VERSION 5.8 ;
BUSBITCHARS "[]" ;
DIVIDERCHAR "/" ;
UNITS
    DATABASE MICRONS 1000 ;
END UNITS

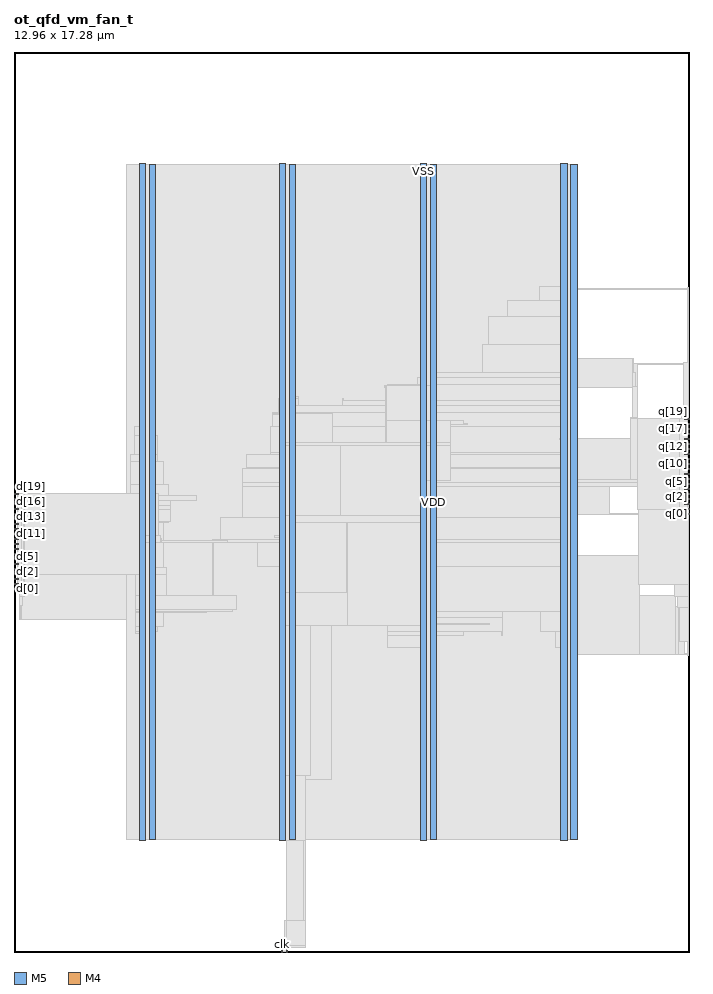
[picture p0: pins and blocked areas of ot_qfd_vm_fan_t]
MACRO ot_qfd_vm_fan_t
  FOREIGN ot_qfd_vm_fan_t 0 0 ;
  CLASS BLOCK ;
  SIZE 12.96 BY 17.28 ;
  PIN clk
    DIRECTION INPUT ;
    USE SIGNAL ;
    PORT
      LAYER M5 ;
        RECT  5.136 0 5.16 0.084 ;
    END
  END clk
  PIN d[0]
    DIRECTION INPUT ;
    USE SIGNAL ;
    PORT
      LAYER M4 ;
        RECT  0 6.96 0.084 6.984 ;
    END
  END d[0]
  PIN d[10]
    DIRECTION INPUT ;
    USE SIGNAL ;
    PORT
      LAYER M4 ;
        RECT  0 7.92 0.084 7.944 ;
    END
  END d[10]
  PIN d[11]
    DIRECTION INPUT ;
    USE SIGNAL ;
    PORT
      LAYER M4 ;
        RECT  0 8.016 0.084 8.04 ;
    END
  END d[11]
  PIN d[12]
    DIRECTION INPUT ;
    USE SIGNAL ;
    PORT
      LAYER M4 ;
        RECT  0 8.112 0.084 8.136 ;
    END
  END d[12]
  PIN d[13]
    DIRECTION INPUT ;
    USE SIGNAL ;
    PORT
      LAYER M4 ;
        RECT  0 8.208 0.084 8.232 ;
    END
  END d[13]
  PIN d[14]
    DIRECTION INPUT ;
    USE SIGNAL ;
    PORT
      LAYER M4 ;
        RECT  0 8.304 0.084 8.328 ;
    END
  END d[14]
  PIN d[15]
    DIRECTION INPUT ;
    USE SIGNAL ;
    PORT
      LAYER M4 ;
        RECT  0 8.4 0.084 8.424 ;
    END
  END d[15]
  PIN d[16]
    DIRECTION INPUT ;
    USE SIGNAL ;
    PORT
      LAYER M4 ;
        RECT  0 8.496 0.084 8.52 ;
    END
  END d[16]
  PIN d[17]
    DIRECTION INPUT ;
    USE SIGNAL ;
    PORT
      LAYER M4 ;
        RECT  0 8.592 0.084 8.616 ;
    END
  END d[17]
  PIN d[18]
    DIRECTION INPUT ;
    USE SIGNAL ;
    PORT
      LAYER M4 ;
        RECT  0 8.688 0.084 8.712 ;
    END
  END d[18]
  PIN d[19]
    DIRECTION INPUT ;
    USE SIGNAL ;
    PORT
      LAYER M4 ;
        RECT  0 8.784 0.084 8.808 ;
    END
  END d[19]
  PIN d[1]
    DIRECTION INPUT ;
    USE SIGNAL ;
    PORT
      LAYER M4 ;
        RECT  0 7.056 0.084 7.08 ;
    END
  END d[1]
  PIN d[2]
    DIRECTION INPUT ;
    USE SIGNAL ;
    PORT
      LAYER M4 ;
        RECT  0 7.152 0.084 7.176 ;
    END
  END d[2]
  PIN d[3]
    DIRECTION INPUT ;
    USE SIGNAL ;
    PORT
      LAYER M4 ;
        RECT  0 7.248 0.084 7.272 ;
    END
  END d[3]
  PIN d[4]
    DIRECTION INPUT ;
    USE SIGNAL ;
    PORT
      LAYER M4 ;
        RECT  0 7.344 0.084 7.368 ;
    END
  END d[4]
  PIN d[5]
    DIRECTION INPUT ;
    USE SIGNAL ;
    PORT
      LAYER M4 ;
        RECT  0 7.44 0.084 7.464 ;
    END
  END d[5]
  PIN d[6]
    DIRECTION INPUT ;
    USE SIGNAL ;
    PORT
      LAYER M4 ;
        RECT  0 7.536 0.084 7.56 ;
    END
  END d[6]
  PIN d[7]
    DIRECTION INPUT ;
    USE SIGNAL ;
    PORT
      LAYER M4 ;
        RECT  0 7.632 0.084 7.656 ;
    END
  END d[7]
  PIN d[8]
    DIRECTION INPUT ;
    USE SIGNAL ;
    PORT
      LAYER M4 ;
        RECT  0 7.728 0.084 7.752 ;
    END
  END d[8]
  PIN d[9]
    DIRECTION INPUT ;
    USE SIGNAL ;
    PORT
      LAYER M4 ;
        RECT  0 7.824 0.084 7.848 ;
    END
  END d[9]
  PIN me_e
    DIRECTION INPUT ;
    USE SIGNAL ;
    PORT
      LAYER M5 ;
        RECT  5.232 0 5.256 0.084 ;
    END
  END me_e
  PIN q[0]
    DIRECTION OUTPUT ;
    USE SIGNAL ;
    PORT
      LAYER M4 ;
        RECT  12.876 8.4 12.96 8.424 ;
    END
  END q[0]
  PIN q[10]
    DIRECTION OUTPUT ;
    USE SIGNAL ;
    PORT
      LAYER M4 ;
        RECT  12.876 9.36 12.96 9.384 ;
    END
  END q[10]
  PIN q[11]
    DIRECTION OUTPUT ;
    USE SIGNAL ;
    PORT
      LAYER M4 ;
        RECT  12.876 9.456 12.96 9.48 ;
    END
  END q[11]
  PIN q[12]
    DIRECTION OUTPUT ;
    USE SIGNAL ;
    PORT
      LAYER M4 ;
        RECT  12.876 9.552 12.96 9.576 ;
    END
  END q[12]
  PIN q[13]
    DIRECTION OUTPUT ;
    USE SIGNAL ;
    PORT
      LAYER M4 ;
        RECT  12.876 9.648 12.96 9.672 ;
    END
  END q[13]
  PIN q[14]
    DIRECTION OUTPUT ;
    USE SIGNAL ;
    PORT
      LAYER M4 ;
        RECT  12.876 9.744 12.96 9.768 ;
    END
  END q[14]
  PIN q[15]
    DIRECTION OUTPUT ;
    USE SIGNAL ;
    PORT
      LAYER M4 ;
        RECT  12.876 9.84 12.96 9.864 ;
    END
  END q[15]
  PIN q[16]
    DIRECTION OUTPUT ;
    USE SIGNAL ;
    PORT
      LAYER M4 ;
        RECT  12.876 9.936 12.96 9.96 ;
    END
  END q[16]
  PIN q[17]
    DIRECTION OUTPUT ;
    USE SIGNAL ;
    PORT
      LAYER M4 ;
        RECT  12.876 10.032 12.96 10.056 ;
    END
  END q[17]
  PIN q[18]
    DIRECTION OUTPUT ;
    USE SIGNAL ;
    PORT
      LAYER M4 ;
        RECT  12.876 10.128 12.96 10.152 ;
    END
  END q[18]
  PIN q[19]
    DIRECTION OUTPUT ;
    USE SIGNAL ;
    PORT
      LAYER M4 ;
        RECT  12.876 10.224 12.96 10.248 ;
    END
  END q[19]
  PIN q[1]
    DIRECTION OUTPUT ;
    USE SIGNAL ;
    PORT
      LAYER M4 ;
        RECT  12.876 8.496 12.96 8.52 ;
    END
  END q[1]
  PIN q[2]
    DIRECTION OUTPUT ;
    USE SIGNAL ;
    PORT
      LAYER M4 ;
        RECT  12.876 8.592 12.96 8.616 ;
    END
  END q[2]
  PIN q[3]
    DIRECTION OUTPUT ;
    USE SIGNAL ;
    PORT
      LAYER M4 ;
        RECT  12.876 8.688 12.96 8.712 ;
    END
  END q[3]
  PIN q[4]
    DIRECTION OUTPUT ;
    USE SIGNAL ;
    PORT
      LAYER M4 ;
        RECT  12.876 8.784 12.96 8.808 ;
    END
  END q[4]
  PIN q[5]
    DIRECTION OUTPUT ;
    USE SIGNAL ;
    PORT
      LAYER M4 ;
        RECT  12.876 8.88 12.96 8.904 ;
    END
  END q[5]
  PIN q[6]
    DIRECTION OUTPUT ;
    USE SIGNAL ;
    PORT
      LAYER M4 ;
        RECT  12.876 8.976 12.96 9 ;
    END
  END q[6]
  PIN q[7]
    DIRECTION OUTPUT ;
    USE SIGNAL ;
    PORT
      LAYER M4 ;
        RECT  12.876 9.072 12.96 9.096 ;
    END
  END q[7]
  PIN q[8]
    DIRECTION OUTPUT ;
    USE SIGNAL ;
    PORT
      LAYER M4 ;
        RECT  12.876 9.168 12.96 9.192 ;
    END
  END q[8]
  PIN q[9]
    DIRECTION OUTPUT ;
    USE SIGNAL ;
    PORT
      LAYER M4 ;
        RECT  12.876 9.264 12.96 9.288 ;
    END
  END q[9]
  PIN VDD
    DIRECTION INOUT ;
    USE POWER ;
    PORT
      LAYER M5 ;
        RECT  10.692 2.151 10.812 15.129 ;
        RECT  7.992 2.151 8.112 15.129 ;
        RECT  5.292 2.151 5.412 15.129 ;
        RECT  2.592 2.151 2.712 15.129 ;
    END
  END VDD
  PIN VSS
    DIRECTION INOUT ;
    USE GROUND ;
    PORT
      LAYER M5 ;
        RECT  10.5 2.137 10.62 15.143 ;
        RECT  7.8 2.137 7.92 15.143 ;
        RECT  5.1 2.137 5.22 15.143 ;
        RECT  2.4 2.137 2.52 15.143 ;
    END
  END VSS
  # OT_OBS_CLOSED layer=M5 d_um=1.536 added=5
  OBS
    LAYER RVTN ;
     RECT  2.16 2.16 10.8 2.295 ;
     RECT  2.16 2.565 10.8 2.835 ;
     RECT  2.16 3.105 10.8 3.375 ;
     RECT  2.16 3.645 10.8 3.915 ;
     RECT  2.16 4.185 10.8 4.455 ;
     RECT  2.16 4.725 10.8 4.995 ;
     RECT  2.16 5.265 10.8 5.535 ;
     RECT  2.16 5.805 10.8 6.075 ;
     RECT  2.16 6.345 10.8 6.615 ;
     RECT  2.16 6.885 10.8 7.155 ;
     RECT  2.16 7.425 10.8 7.695 ;
     RECT  2.16 7.965 10.8 8.235 ;
     RECT  2.16 8.505 10.8 8.775 ;
     RECT  2.16 9.045 10.8 9.315 ;
     RECT  2.16 9.585 10.8 9.855 ;
     RECT  2.16 10.125 10.8 10.395 ;
     RECT  2.16 10.665 10.8 10.935 ;
     RECT  2.16 11.205 10.8 11.475 ;
     RECT  2.16 11.745 10.8 12.015 ;
     RECT  2.16 12.285 10.8 12.555 ;
     RECT  2.16 12.825 10.8 13.095 ;
     RECT  2.16 13.365 10.8 13.635 ;
     RECT  2.16 13.905 10.8 14.175 ;
     RECT  2.16 14.445 10.8 14.715 ;
     RECT  2.16 14.985 10.8 15.12 ;
    LAYER RVTP ;
     RECT  2.16 2.295 10.8 2.565 ;
     RECT  2.16 2.835 10.8 3.105 ;
     RECT  2.16 3.375 10.8 3.645 ;
     RECT  2.16 3.915 10.8 4.185 ;
     RECT  2.16 4.455 10.8 4.725 ;
     RECT  2.16 4.995 10.8 5.265 ;
     RECT  2.16 5.535 10.8 5.805 ;
     RECT  2.16 6.075 10.8 6.345 ;
     RECT  2.16 6.615 10.8 6.885 ;
     RECT  2.16 7.155 10.8 7.425 ;
     RECT  2.16 7.695 10.8 7.965 ;
     RECT  2.16 8.235 10.8 8.505 ;
     RECT  2.16 8.775 10.8 9.045 ;
     RECT  2.16 9.315 10.8 9.585 ;
     RECT  2.16 9.855 10.8 10.125 ;
     RECT  2.16 10.395 10.8 10.665 ;
     RECT  2.16 10.935 10.8 11.205 ;
     RECT  2.16 11.475 10.8 11.745 ;
     RECT  2.16 12.015 10.8 12.285 ;
     RECT  2.16 12.555 10.8 12.825 ;
     RECT  2.16 13.095 10.8 13.365 ;
     RECT  2.16 13.635 10.8 13.905 ;
     RECT  2.16 14.175 10.8 14.445 ;
     RECT  2.16 14.715 10.8 14.985 ;
    LAYER M1 ;
     RECT  2.16 2.151 10.8 15.129 ;
    LAYER M2 ;
     RECT  0.103 6.39 0.139 6.408 ;
     RECT  0.103 7.398 0.139 7.416 ;
     RECT  0.139 6.39 2.16 7.416 ;
     RECT  2.16 2.151 10.8 15.129 ;
     RECT  10.8 2.421 10.812 14.859 ;
     RECT  10.812 8.406 11.435 9.846 ;
     RECT  10.812 10.836 11.903 11.394 ;
     RECT  11.435 9.216 11.939 9.846 ;
     RECT  11.939 9.216 11.975 9.774 ;
     RECT  11.903 10.836 11.975 11.304 ;
     RECT  10.812 5.706 12.011 7.614 ;
     RECT  12.011 7.596 12.047 7.614 ;
     RECT  11.435 8.406 12.083 8.424 ;
     RECT  12.011 5.706 12.695 6.84 ;
     RECT  12.695 5.706 12.767 6.642 ;
     RECT  12.775 8.478 12.847 8.496 ;
     RECT  12.767 5.706 12.875 6.264 ;
     RECT  12.847 8.478 12.875 8.604 ;
     RECT  11.975 11.286 12.875 11.304 ;
     RECT  12.875 5.706 12.947 5.724 ;
     RECT  12.875 8.586 12.947 8.604 ;
     RECT  12.811 10.251 12.947 10.269 ;
     RECT  10.812 12.726 12.947 12.744 ;
    LAYER M3 ;
     RECT  5.256 0.571 5.274 2.143 ;
     RECT  2.415 2.143 2.505 2.413 ;
     RECT  5.115 2.143 5.274 2.413 ;
     RECT  7.815 2.143 7.905 2.413 ;
     RECT  10.515 2.143 10.605 2.413 ;
     RECT  5.115 2.413 5.397 2.641 ;
     RECT  5.115 2.641 5.454 3.307 ;
     RECT  7.815 2.413 8.097 5.845 ;
     RECT  10.515 2.413 10.797 5.845 ;
     RECT  12.924 5.701 12.942 5.971 ;
     RECT  7.164 5.845 8.097 6.079 ;
     RECT  2.415 2.413 2.697 6.115 ;
     RECT  2.34 6.115 2.697 6.151 ;
     RECT  7.164 6.079 8.622 6.151 ;
     RECT  9.36 6.079 9.378 6.151 ;
     RECT  10.404 5.845 10.797 6.151 ;
     RECT  2.34 6.151 2.754 6.241 ;
     RECT  5.115 3.307 6.102 6.421 ;
     RECT  7.164 6.151 9.378 6.421 ;
     RECT  2.34 6.241 2.862 6.511 ;
     RECT  2.34 6.511 3.69 6.547 ;
     RECT  5.115 6.421 9.378 6.547 ;
     RECT  10.116 6.151 10.797 6.547 ;
     RECT  2.34 6.547 4.194 6.583 ;
     RECT  12.78 5.971 12.942 6.619 ;
     RECT  0.108 6.385 0.126 6.655 ;
     RECT  0.108 6.655 0.162 6.817 ;
     RECT  12.744 6.619 12.942 6.817 ;
     RECT  2.34 6.583 4.266 6.845 ;
     RECT  12.672 6.817 12.942 7.051 ;
     RECT  0.108 6.817 0.198 7.181 ;
     RECT  2.34 6.845 2.934 7.243 ;
     RECT  2.304 7.243 2.934 7.385 ;
     RECT  5.115 6.547 10.797 7.393 ;
     RECT  0.108 7.181 0.162 7.565 ;
     RECT  3.816 6.845 3.834 7.867 ;
     RECT  4.68 7.393 10.797 7.867 ;
     RECT  3.816 7.867 10.797 7.925 ;
     RECT  0.144 7.565 0.162 7.997 ;
     RECT  2.304 7.385 2.862 8.239 ;
     RECT  2.304 8.239 2.97 8.275 ;
     RECT  3.96 7.925 10.797 8.339 ;
     RECT  2.304 8.275 3.006 8.491 ;
     RECT  2.268 8.491 3.006 8.581 ;
     RECT  11.988 7.051 12.942 8.609 ;
     RECT  11.988 8.609 12.87 8.621 ;
     RECT  2.232 8.581 3.006 8.671 ;
     RECT  2.232 8.671 3.51 8.771 ;
     RECT  11.988 8.621 12.798 8.813 ;
     RECT  4.392 8.339 10.797 8.941 ;
     RECT  11.988 8.813 12.762 8.941 ;
     RECT  2.232 8.771 2.97 8.969 ;
     RECT  4.392 8.941 12.762 9.005 ;
     RECT  4.392 9.005 12.078 9.275 ;
     RECT  4.464 9.275 12.078 9.293 ;
     RECT  2.232 8.969 2.862 9.419 ;
     RECT  2.232 9.419 2.754 9.545 ;
     RECT  4.464 9.293 11.97 9.545 ;
     RECT  4.932 9.545 11.97 9.581 ;
     RECT  2.304 9.545 2.754 9.923 ;
     RECT  2.304 9.923 2.697 10.085 ;
     RECT  4.932 9.581 10.797 10.085 ;
     RECT  12.852 10.027 12.87 10.219 ;
     RECT  12.816 10.219 12.87 10.246 ;
     RECT  11.844 9.581 11.97 10.253 ;
     RECT  12.816 10.246 12.942 10.274 ;
     RECT  4.968 10.085 10.797 10.349 ;
     RECT  5.076 10.349 10.797 10.499 ;
     RECT  6.3 10.499 10.797 10.589 ;
     RECT  5.076 10.499 5.454 10.625 ;
     RECT  6.3 10.589 6.318 10.625 ;
     RECT  5.115 10.625 5.454 10.661 ;
     RECT  11.88 10.253 11.97 10.859 ;
     RECT  7.164 10.589 10.797 10.895 ;
     RECT  7.74 10.895 10.797 11.039 ;
     RECT  7.815 11.039 10.797 11.129 ;
     RECT  11.88 10.859 11.934 11.129 ;
     RECT  12.852 10.274 12.942 11.309 ;
     RECT  11.88 11.129 11.898 11.399 ;
     RECT  9 11.129 10.797 11.669 ;
     RECT  9.108 11.669 10.797 12.209 ;
     RECT  9.468 12.209 10.797 12.515 ;
     RECT  12.924 11.309 12.942 12.749 ;
     RECT  10.08 12.515 10.797 12.785 ;
     RECT  2.415 10.085 2.697 14.867 ;
     RECT  5.115 10.661 5.397 14.867 ;
     RECT  7.815 11.129 8.097 14.867 ;
     RECT  10.515 12.785 10.797 14.867 ;
     RECT  2.415 14.867 2.505 15.137 ;
     RECT  5.115 14.867 5.205 15.137 ;
     RECT  7.815 14.867 7.905 15.137 ;
     RECT  10.515 14.867 10.605 15.137 ;
    LAYER M4 ;
     RECT  0.06 6.96 0.137 8.808 ;
     RECT  0.137 7.056 0.173 8.808 ;
     RECT  0.173 7.152 0.209 8.808 ;
     RECT  0.209 7.248 2.408 8.808 ;
     RECT  2.408 2.148 2.512 15.132 ;
     RECT  2.512 2.418 2.704 14.862 ;
     RECT  2.704 7.872 2.765 8.808 ;
     RECT  2.765 7.872 2.819 7.992 ;
     RECT  2.819 7.872 2.839 7.944 ;
     RECT  2.839 7.872 4.097 7.896 ;
     RECT  4.993 7.968 5.108 7.992 ;
     RECT  4.957 10.32 5.108 10.344 ;
     RECT  5.125 0.096 5.201 0.12 ;
     RECT  5.108 2.148 5.212 15.132 ;
     RECT  5.201 0.096 5.285 0.6 ;
     RECT  5.212 2.418 5.404 14.862 ;
     RECT  5.285 0.096 5.603 0.12 ;
     RECT  5.404 3.408 5.699 3.432 ;
     RECT  5.404 9.744 6.113 10.344 ;
     RECT  5.404 6.288 6.419 8.616 ;
     RECT  6.113 9.744 7.141 9.768 ;
     RECT  7.109 10.848 7.141 10.872 ;
     RECT  6.419 6.288 7.808 6.888 ;
     RECT  6.419 8.208 7.808 8.616 ;
     RECT  7.141 9.744 7.808 10.872 ;
     RECT  7.808 2.148 7.912 15.132 ;
     RECT  7.912 2.418 8.104 14.862 ;
     RECT  8.104 9.072 8.387 9.096 ;
     RECT  8.104 10.128 8.633 10.2 ;
     RECT  8.633 10.128 8.705 10.152 ;
     RECT  8.104 6.288 9.137 6.312 ;
     RECT  10.465 9.84 10.508 9.864 ;
     RECT  10.508 2.148 10.612 15.132 ;
     RECT  10.612 2.418 10.804 14.862 ;
     RECT  10.804 9.072 11.833 9.864 ;
     RECT  11.833 9.072 11.977 10.248 ;
     RECT  11.977 8.496 12.769 10.248 ;
     RECT  12.769 8.4 12.924 10.248 ;
    LAYER M5 ;
     RECT  5.136 0.016 5.256 0.085 ;
     RECT  5.136 0.085 5.592 0.131 ;
     RECT  5.232 0.131 5.592 0.611 ;
     RECT  5.568 0.611 5.592 2.137 ;
     RECT  2.4 2.137 2.52 2.151 ;
     RECT  7.8 2.137 7.92 2.151 ;
     RECT  10.5 2.137 10.62 2.151 ;
     RECT  5.1 2.137 5.592 3.397 ;
     RECT  5.1 3.397 5.688 6.277 ;
     RECT  5.1 6.277 6.408 6.899 ;
     RECT  2.4 2.151 2.712 7.861 ;
     RECT  2.4 7.861 2.808 8.003 ;
     RECT  6.384 6.899 6.408 8.243 ;
     RECT  5.1 6.899 5.412 8.389 ;
     RECT  7.8 2.151 8.112 9.061 ;
     RECT  5.1 8.389 6.264 9.733 ;
     RECT  7.8 9.061 8.376 9.733 ;
     RECT  5.1 9.733 8.376 9.779 ;
     RECT  7.152 9.779 8.376 10.211 ;
     RECT  7.152 10.211 8.112 10.883 ;
     RECT  2.4 8.003 2.712 15.129 ;
     RECT  5.1 9.779 5.412 15.129 ;
     RECT  7.8 10.883 8.112 15.129 ;
     RECT  10.5 2.151 10.812 15.129 ;
     RECT  2.4 15.129 2.52 15.143 ;
     RECT  5.1 15.129 5.22 15.143 ;
     RECT  7.8 15.129 7.92 15.143 ;
     RECT  10.5 15.129 10.62 15.143 ;
     RECT  5.232 0.611 5.568 2.137 ;
     RECT  6.408 6.277 7.8 8.243 ;
     RECT  5.412 6.899 6.384 8.243 ;
     RECT  5.412 8.243 7.8 8.389 ;
     RECT  6.264 8.389 7.8 9.733 ;
  END
END ot_qfd_vm_fan_t
END LIBRARY
